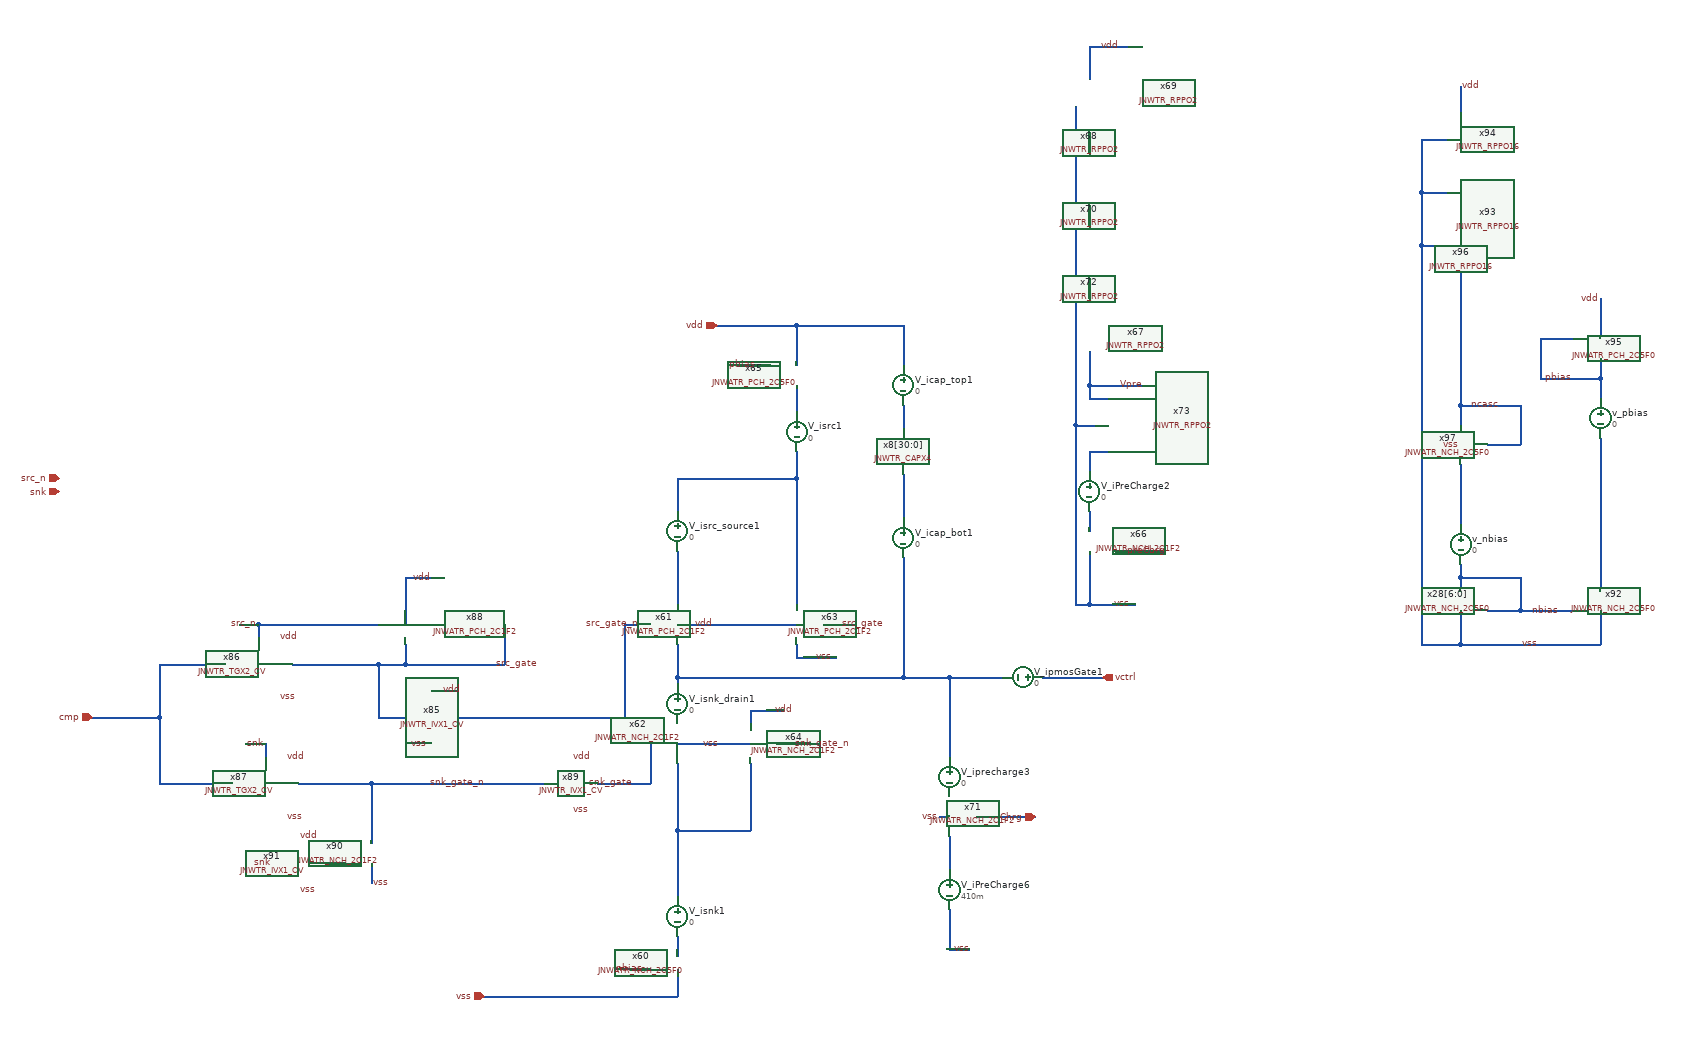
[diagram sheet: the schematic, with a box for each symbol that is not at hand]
v {xschem version=3.4.6 file_version=1.2}
G {}
K {}
V {}
S {}
E {}
N -120 -1190 0 -1190 {
lab=vdd}
N 0 -1190 0 -1130 {
lab=vdd}
N -180 -220 -180 -180 {
lab=vss}
N -90 -1130 -40 -1130 {
lab=pbias}
N -250 -220 -220 -220 {
lab=nbias}
N 440 -1100 520 -1100 {
lab=Vpre}
N -180 -710 -180 -660 {
lab=#net1}
N 0 -710 0 -690 {
lab=vss}
N 0 -690 60 -690 {
lab=vss}
N 40 -740 65 -740 {
lab=src_gate}
N -70 -610 -70 -590 {
lab=vdd}
N -70 -610 -20 -610 {
lab=vdd}
N -30 -560 20 -560 {
lab=snk_gate_n}
N -180 -270 -180 -240 {
lab=#net2}
N 0 -1100 0 -1060 {
lab=#net3}
N 440 -850 440 -770 {
lab=vss}
N 480 -850 550 -850 {
lab=preChrg}
N 440 -910 440 -880 {
lab=#net4}
N 440 -1000 440 -970 {
lab=#net5}
N 440 -770 510 -770 {
lab=vss}
N 420 -770 440 -770 {
lab=vss}
N 440 -1480 440 -1450 {
lab=#net6}
N 440 -1610 440 -1560 {
lab=vdd}
N 440 -1610 500 -1610 {
lab=vdd}
N 440 -1370 440 -1340 {
lab=#net7}
N -180 -660 -180 -650 {
lab=#net1}
N -180 -960 0 -960 {
lab=#net8}
N 0 -1000 0 -960 {
lab=#net8}
N -470 -180 -180 -180 {
lab=vss}
N 0 -1190 160 -1190 {
lab=vdd}
N -180 -740 0 -740 {
lab=vdd}
N -180 -560 -70 -560 {
lab=vss}
N -180 -430 -180 -330 {
lab=#net9}
N -70 -530 -70 -430 {
lab=#net9}
N -180 -430 -70 -430 {
lab=#net9}
N -180 -530 -180 -430 {
lab=#net9}
N 0 -960 0 -770 {
lab=#net8}
N 160 -965 160 -900 {
lab=#net10}
N 160 -840 160 -660 {
lab=#net1}
N -180 -660 160 -660 {
lab=#net1}
N 230 -660 310 -660 {
lab=#net1}
N 370 -660 460 -660 {
lab=vctrl}
N 160 -1070 160 -1035 {
lab=#net11}
N 160 -1190 160 -1130 {
lab=vdd}
N -180 -960 -180 -910 {
lab=#net8}
N -180 -850 -180 -770 {
lab=#net12}
N 270 -450 360 -450 {
lab=preChrg}
N 215 -450 230 -450 {
lab=vss}
N 230 -420 230 -370 {
lab=#net13}
N 230 -660 230 -540 {
lab=#net1}
N 160 -660 230 -660 {
lab=#net1}
N 440 -1100 440 -1080 {lab=Vpre}
N 420 -1040 420 -770 {
lab=vss}
N 440 -1080 470 -1080 {lab=Vpre}
N 440 -1000 470 -1000 {lab=#net5}
N 420 -1040 450 -1040 {lab=vss}
N 440 -1150 440 -1100 {lab=Vpre}
N 440 -1260 440 -1230 {lab=#net14}
N 420 -1520 420 -1040 {
lab=vss}
N 230 -310 230 -250 {lab=vss}
N 230 -250 260 -250 {lab=vss}
N -1060 -600 -960 -600 {lab=cmp}
N -960 -600 -960 -500 {lab=cmp}
N -960 -680 -960 -600 {lab=cmp}
N -590 -680 -440 -680 {
lab=src_gate}
N -555 -560 -550 -560 {
lab=vss}
N -550 -640 -535 -640 {
lab=vdd}
N -630 -680 -630 -600 {
lab=src_gate}
N -630 -600 -590 -600 {
lab=src_gate}
N -510 -600 -260 -600 {
lab=src_gate_n}
N -810 -740 -810 -720 {lab=src_n}
N -840 -740 -810 -740 {lab=src_n}
N -760 -680 -630 -680 {lab=src_gate}
N -590 -710 -590 -680 {lab=src_gate}
N -630 -680 -590 -680 {
lab=src_gate}
N -590 -810 -590 -740 {lab=vdd}
N -590 -810 -550 -810 {lab=vdd}
N -810 -740 -630 -740 {lab=src_n}
N -800 -560 -800 -540 {lab=snk}
N -830 -560 -800 -560 {lab=snk}
N -640 -500 -380 -500 {lab=snk_gate_n}
N -960 -680 -860 -680 {lab=cmp}
N -960 -500 -850 -500 {lab=cmp}
N -640 -500 -640 -410 {lab=snk_gate_n}
N -750 -500 -640 -500 {lab=snk_gate_n}
N -640 -380 -640 -350 {lab=vss}
N -710 -380 -680 -380 {lab=#net15}
N -440 -740 -440 -680 {lab=src_gate}
N -300 -500 -220 -500 {lab=snk_gate}
N 1000 -810 1090 -810 {
lab=nbias}
N 1000 -810 1000 -790 {
lab=nbias}
N 1210 -1140 1210 -1110 {
lab=pbias}
N 1120 -1110 1210 -1110 {
lab=pbias}
N 1120 -1170 1120 -1110 {
lab=pbias}
N 1120 -1170 1170 -1170 {
lab=pbias}
N 1210 -1230 1210 -1170 {
lab=vdd}
N 1000 -760 1000 -710 {
lab=vss}
N 940 -710 1000 -710 {
lab=vss}
N 1090 -810 1090 -760 {
lab=nbias}
N 1040 -760 1090 -760 {
lab=nbias}
N 1210 -760 1210 -710 {
lab=vss}
N 1090 -760 1170 -760 {
lab=nbias}
N 1210 -1110 1210 -1080 {
lab=pbias}
N 940 -1310 980 -1310 {
lab=vss}
N 1000 -1550 1000 -1510 {
lab=vdd}
N 940 -1390 940 -1310 {
lab=vss}
N 940 -1310 940 -710 {
lab=vss}
N 1000 -710 1210 -710 {
lab=vss}
N 940 -1390 980 -1390 {
lab=vss}
N 940 -1470 940 -1390 {
lab=vss}
N 1000 -830 1000 -810 {lab=nbias}
N 1210 -1020 1210 -790 {lab=#net16}
N 1000 -1270 1000 -1070 {lab=ncasc}
N 1000 -1070 1090 -1070 {lab=ncasc}
N 1090 -1070 1090 -1010 {lab=ncasc}
N 1000 -1070 1000 -1040 {lab=ncasc}
N 1040 -1010 1090 -1010 {lab=ncasc}
N 1000 -980 1000 -890 {lab=#net17}
N 940 -1470 980 -1470 {lab=vss}
N -260 -740 -260 -600 {lab=src_gate_n}
N -260 -740 -220 -740 {lab=src_gate_n}
N -220 -560 -220 -500 {lab=snk_gate}
C {devices/ipin.sym} -120 -1190 0 0 {name=p113 lab=vdd}
C {devices/opin.sym} 460 -660 0 0 {name=p114 lab=vctrl}
C {devices/ipin.sym} -470 -180 0 0 {name=p115 lab=vss
}
C {JNW_TR_SKY130A/JNWTR_CAPX4.sym} 160 -975 0 0 {name=x8[30:0]}
C {devices/ipin.sym} 360 -450 2 0 {name=p116 lab=preChrg
}
C {devices/lab_wire.sym} 455 -1610 0 1 {name=p117 sig_type=std_logic lab=vdd}
C {JNW_ATR_SKY130A/JNWATR_NCH_2C5F0.sym} -220 -220 0 0 {name=x60 }
C {devices/lab_wire.sym} -155 -740 0 1 {name=p118 sig_type=std_logic lab=vdd}
C {devices/lab_wire.sym} 475 -770 0 1 {name=p119 sig_type=std_logic lab=vss}
C {devices/lab_wire.sym} 485 -1100 0 1 {name=p120 sig_type=std_logic lab=Vpre}
C {JNW_ATR_SKY130A/JNWATR_PCH_2C1F2.sym} -220 -740 0 0 {name=x61 }
C {JNW_ATR_SKY130A/JNWATR_NCH_2C1F2.sym} -220 -560 0 0 {name=x62 }
C {JNW_ATR_SKY130A/JNWATR_PCH_2C1F2.sym} 40 -740 0 1 {name=x63 }
C {devices/lab_wire.sym} 55 -690 0 0 {name=p121 sig_type=std_logic lab=vss}
C {devices/lab_wire.sym} 65 -740 0 1 {name=p122 sig_type=std_logic lab=src_gate}
C {JNW_ATR_SKY130A/JNWATR_NCH_2C1F2.sym} -30 -560 0 1 {name=x64 }
C {devices/lab_wire.sym} -115 -560 0 0 {name=p123 sig_type=std_logic lab=vss}
C {devices/lab_wire.sym} -5 -560 0 1 {name=p124 sig_type=std_logic lab=snk_gate_n}
C {devices/vsource.sym} 0 -1030 0 0 {name=V_isrc1 value=0 savecurrent=true}
C {devices/vsource.sym} -180 -300 0 0 {name=V_isnk1 value=0 savecurrent=true}
C {JNW_ATR_SKY130A/JNWATR_PCH_2C5F0.sym} -40 -1130 0 0 {name=x65 }
C {devices/vsource.sym} 440 -940 0 0 {name=V_iPreCharge2 value=0 savecurrent=true}
C {JNW_ATR_SKY130A/JNWATR_NCH_2C1F2.sym} 480 -850 0 1 {name=x66 }
C {devices/lab_wire.sym} 495 -850 0 1 {name=p125 sig_type=std_logic lab=preChrg}
C {JNW_TR_SKY130A/JNWTR_RPPO2.sym} 440 -1080 1 0 {name=x67 }
C {JNW_TR_SKY130A/JNWTR_RPPO2.sym} 440 -1450 1 0 {name=x68 }
C {JNW_TR_SKY130A/JNWTR_RPPO2.sym} 440 -1560 1 0 {name=x69 }
C {JNW_TR_SKY130A/JNWTR_RPPO2.sym} 440 -1340 1 0 {name=x70 }
C {devices/vsource.sym} -180 -620 0 0 {name=V_isnk_drain1 value=0 savecurrent=true}
C {devices/vsource.sym} -180 -880 0 0 {name=V_isrc_source1 value=0 savecurrent=true}
C {devices/lab_wire.sym} -35 -610 0 1 {name=p126 sig_type=std_logic lab=vdd}
C {devices/vsource.sym} 160 -870 0 0 {name=V_icap_bot1 value=0 savecurrent=true}
C {devices/vsource.sym} 230 -510 0 0 {name=V_iprecharge3 value=0 savecurrent=true}
C {devices/vsource.sym} 340 -660 1 0 {name=V_ipmosGate1 value=0 savecurrent=true}
C {devices/vsource.sym} 160 -1100 0 0 {name=V_icap_top1 value=0 savecurrent=true}
C {JNW_ATR_SKY130A/JNWATR_NCH_2C1F2.sym} 270 -450 0 1 {name=x71 }
C {devices/lab_wire.sym} 215 -450 0 0 {name=p127 sig_type=std_logic lab=vss}
C {JNW_TR_SKY130A/JNWTR_RPPO2.sym} 440 -1230 1 0 {name=x72 }
C {JNW_TR_SKY130A/JNWTR_RPPO2.sym} 470 -1080 1 0 {name=x73 }
C {devices/ipin.sym} -1110 -940 0 0 {name=p128 lab=snk
}
C {devices/ipin.sym} -1110 -960 0 0 {name=p129 lab=src_n}
C {devices/lab_wire.sym} -235 -740 0 0 {name=p132 sig_type=std_logic lab=src_gate_n}
C {devices/lab_wire.sym} -245 -500 0 0 {name=p133 sig_type=std_logic lab=snk_gate}
C {devices/vsource.sym} 230 -340 0 0 {name=V_iPreCharge6 value=410m savecurrent=true}
C {devices/lab_wire.sym} 235 -250 0 1 {name=p155 sig_type=std_logic lab=vss}
C {devices/ipin.sym} -1060 -600 0 0 {name=p156 lab=cmp}
C {devices/lab_wire.sym} -455 -680 0 1 {name=p157 sig_type=std_logic lab=src_gate}
C {JNW_TR_SKY130A/JNWTR_IVX1_CV.sym} -590 -600 0 0 {name=x85 }
C {devices/lab_wire.sym} -535 -640 0 1 {name=p158 sig_type=std_logic lab=vdd}
C {devices/lab_wire.sym} -555 -560 0 0 {name=p159 sig_type=std_logic lab=vss}
C {devices/lab_wire.sym} -555 -500 0 1 {name=p160 sig_type=std_logic lab=snk_gate_n}
C {JNW_TR_SKY130A/JNWTR_TGX2_CV.sym} -870 -680 0 0 {name=x86 }
C {devices/lab_wire.sym} -780 -720 0 1 {name=p161 sig_type=std_logic lab=vdd

}
C {devices/lab_wire.sym} -780 -630 0 1 {name=p162 sig_type=std_logic lab=vss

}
C {devices/lab_wire.sym} -810 -740 0 0 {name=p163 sig_type=std_logic lab=src_n

}
C {devices/lab_wire.sym} -580 -810 0 1 {name=p164 sig_type=std_logic lab=vdd

}
C {JNW_TR_SKY130A/JNWTR_TGX2_CV.sym} -860 -500 0 0 {name=x87 }
C {devices/lab_wire.sym} -770 -540 0 1 {name=p165 sig_type=std_logic lab=vdd

}
C {devices/lab_wire.sym} -770 -450 0 1 {name=p166 sig_type=std_logic lab=vss

}
C {devices/lab_wire.sym} -800 -560 0 0 {name=p167 sig_type=std_logic lab=snk

}
C {JNW_ATR_SKY130A/JNWATR_PCH_2C1F2.sym} -630 -740 0 0 {name=x88 }
C {JNW_TR_SKY130A/JNWTR_IVX1_CV.sym} -380 -500 0 0 {name=x89 }
C {devices/lab_wire.sym} -340 -460 0 1 {name=p168 sig_type=std_logic lab=vss

}
C {devices/lab_wire.sym} -340 -540 0 1 {name=p169 sig_type=std_logic lab=vdd

}
C {JNW_ATR_SKY130A/JNWATR_NCH_2C1F2.sym} -680 -380 0 0 {name=x90 }
C {devices/lab_wire.sym} -640 -350 0 1 {name=p170 sig_type=std_logic lab=vss

}
C {JNW_TR_SKY130A/JNWTR_IVX1_CV.sym} -790 -380 0 0 {name=x91 }
C {devices/lab_wire.sym} -750 -340 0 1 {name=p171 sig_type=std_logic lab=vss

}
C {devices/lab_wire.sym} -750 -420 0 1 {name=p172 sig_type=std_logic lab=vdd

}
C {devices/lab_wire.sym} -790 -380 0 0 {name=p173 sig_type=std_logic lab=snk

}
C {devices/lab_wire.sym} 1170 -1110 0 0 {name=p174 sig_type=std_logic lab=pbias}
C {devices/lab_wire.sym} 1000 -1550 0 1 {name=p175 sig_type=std_logic lab=vdd}
C {devices/lab_wire.sym} 1090 -710 0 1 {name=p176 sig_type=std_logic lab=vss}
C {JNW_ATR_SKY130A/JNWATR_NCH_2C5F0.sym} 1040 -760 0 1 {name=x28[6:0]}
C {devices/lab_wire.sym} 1210 -1230 0 0 {name=p177 sig_type=std_logic lab=vdd}
C {JNW_ATR_SKY130A/JNWATR_NCH_2C5F0.sym} 1170 -760 0 0 {name=x92 }
C {devices/lab_wire.sym} 1150 -760 0 0 {name=p178 sig_type=std_logic lab=nbias}
C {devices/vsource.sym} 1000 -860 0 0 {name=v_nbias value=0 savecurrent=true}
C {devices/vsource.sym} 1210 -1050 0 0 {name=v_pbias value=0 savecurrent=true}
C {JNW_TR_SKY130A/JNWTR_RPPO16.sym} 1000 -1350 1 1 {name=x93 }
C {JNW_TR_SKY130A/JNWTR_RPPO16.sym} 1000 -1430 1 1 {name=x94 }
C {JNW_ATR_SKY130A/JNWATR_PCH_2C5F0.sym} 1170 -1170 0 0 {name=x95 }
C {JNW_TR_SKY130A/JNWTR_RPPO16.sym} 1000 -1270 1 1 {name=x96 }
C {JNW_ATR_SKY130A/JNWATR_NCH_2C5F0.sym} 1040 -1010 0 1 {name=x97 }
C {devices/lab_wire.sym} 1000 -1010 0 0 {name=p179 sig_type=std_logic lab=vss}
C {devices/lab_wire.sym} -60 -1130 0 0 {name=p180 sig_type=std_logic lab=pbias}
C {devices/lab_wire.sym} -230 -220 0 0 {name=p181 sig_type=std_logic lab=nbias}
C {devices/lab_wire.sym} 1060 -1070 0 0 {name=p182 sig_type=std_logic lab=ncasc}
